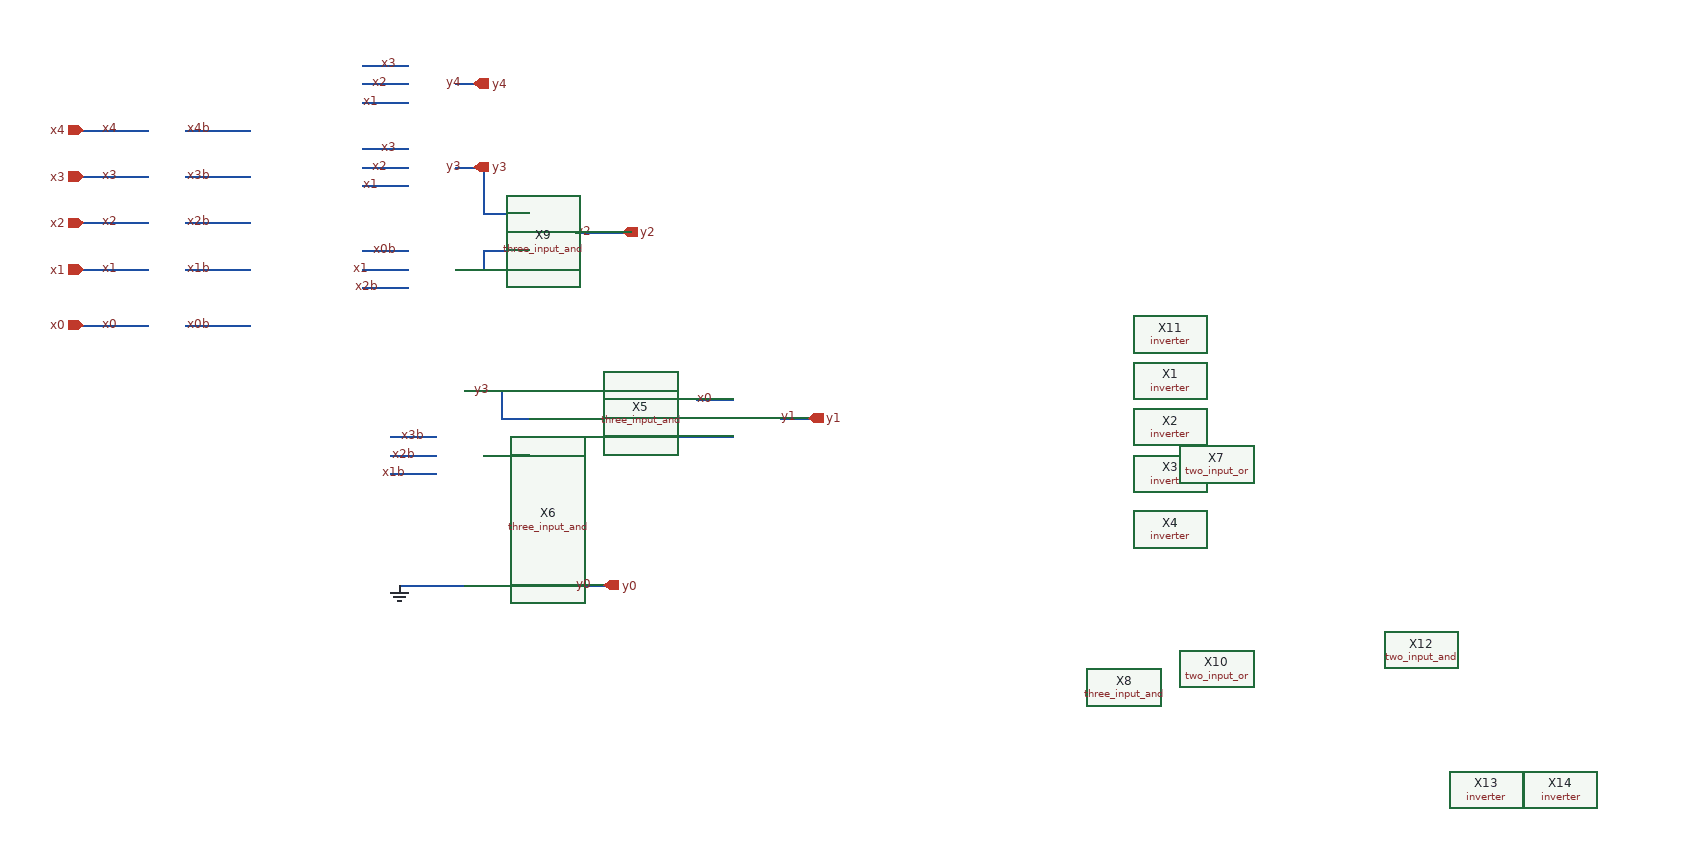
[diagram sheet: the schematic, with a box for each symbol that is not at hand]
v {xschem version=2.9.9 file_version=1.2 }
G {}
K {}
V {}
S {}
E {}
N -700 -240 -670 -240 { lab=x3}
N -630 -240 -580 -240 { lab=x3b}
N -750 -240 -700 -240 { lab=x3}
N -580 -240 -560 -240 { lab=x3b}
N -700 -190 -670 -190 { lab=x2}
N -630 -190 -580 -190 { lab=x2b}
N -750 -190 -700 -190 { lab=x2}
N -580 -190 -560 -190 { lab=x2b}
N -700 -140 -670 -140 { lab=x1}
N -630 -140 -580 -140 { lab=x1b}
N -750 -140 -700 -140 { lab=x1}
N -580 -140 -560 -140 { lab=x1b}
N -700 -80 -670 -80 { lab=x0}
N -630 -80 -580 -80 { lab=x0b}
N -750 -80 -700 -80 { lab=x0}
N -580 -80 -560 -80 { lab=x0b}
N -440 -270 -390 -270 { lab=x3}
N -440 -250 -390 -250 { lab=x2}
N -440 -230 -390 -230 { lab=x1}
N -340 -250 -310 -250 { lab=y3}
N -440 -160 -390 -160 { lab=x0b}
N -440 -140 -390 -140 { lab=x1}
N -440 -120 -390 -120 { lab=x2b}
N -340 -140 -310 -140 { lab=#net1}
N -310 -250 -310 -200 { lab=y3}
N -310 -200 -280 -200 { lab=y3}
N -280 -200 -260 -200 { lab=y3}
N -310 -160 -310 -140 { lab=#net1}
N -310 -160 -260 -160 { lab=#net1}
N -210 -180 -180 -180 { lab=y2}
N -330 -10 -290 -10 { lab=y3}
N -290 -10 -290 20 { lab=y3}
N -290 20 -260 20 { lab=y3}
N -300 60 -260 60 { lab=#net2}
N -210 40 -170 40 { lab=#net3}
N -170 40 -40 40 { lab=#net3}
N -80 0 -40 0 { lab=x0}
N 10 20 50 20 { lab=y1}
N -400 200 -330 200 { lab=GND}
N -290 200 -250 200 { lab=#net4}
N -210 200 -170 200 { lab=y0}
N -180 -180 -150 -180 { lab=y2}
N -410 40 -360 40 { lab=x3b}
N -410 60 -360 60 { lab=x2b}
N -410 80 -360 80 { lab=x1b}
N -310 60 -300 60 { lab=#net2}
N -440 -360 -390 -360 { lab=x3}
N -440 -340 -390 -340 { lab=x2}
N -440 -320 -390 -320 { lab=x1}
N -340 -340 -310 -340 { lab=y4}
N -700 -290 -670 -290 { lab=x4}
N -630 -290 -580 -290 { lab=x3b}
N -750 -290 -700 -290 { lab=x4}
N -580 -290 -560 -290 { lab=x3b}
C {/home/vinodhini/Documents/inverter.sym} 430 -20 0 0 {name=X1}
C {/home/vinodhini/Documents/inverter.sym} 430 30 0 0 {name=X2}
C {/home/vinodhini/Documents/inverter.sym} 430 80 0 0 {name=X3}
C {/home/vinodhini/Documents/inverter.sym} 430 140 0 0 {name=X4}
C {devices/lab_pin.sym} -700 -80 1 0 {name=l1 sig_type=std_logic lab=x0}
C {devices/lab_pin.sym} -700 -140 1 0 {name=l2 sig_type=std_logic lab=x1}
C {devices/lab_pin.sym} -700 -190 1 0 {name=l3 sig_type=std_logic lab=x2}
C {devices/lab_pin.sym} -700 -240 1 0 {name=l4 sig_type=std_logic lab=x3}
C {devices/lab_pin.sym} -600 -80 1 0 {name=l5 sig_type=std_logic lab=x0b}
C {devices/lab_pin.sym} -600 -140 1 0 {name=l6 sig_type=std_logic lab=x1b}
C {devices/lab_pin.sym} -600 -190 1 0 {name=l7 sig_type=std_logic lab=x2b}
C {devices/lab_pin.sym} -600 -240 1 0 {name=l8 sig_type=std_logic lab=x3b}
C {/home/vinodhini/Documents/three_input_and.symbol} 350 0 0 0 {name=X5}
C {devices/lab_pin.sym} -400 -270 1 0 {name=l9 sig_type=std_logic lab=x3}
C {devices/lab_pin.sym} -410 -250 1 0 {name=l10 sig_type=std_logic lab=x2}
C {devices/lab_pin.sym} -420 -230 1 0 {name=l11 sig_type=std_logic lab=x1}
C {devices/lab_pin.sym} -330 -250 1 0 {name=l12 sig_type=std_logic lab=y3}
C {/home/vinodhini/Documents/three_input_and.symbol} 350 110 0 0 {name=X6}
C {devices/lab_pin.sym} -400 -160 1 0 {name=l13 sig_type=std_logic lab=x0b}
C {devices/lab_pin.sym} -420 -120 1 0 {name=l15 sig_type=std_logic lab=x2b}
C {devices/lab_pin.sym} -430 -140 1 0 {name=l14 sig_type=std_logic lab=x1}
C {devices/lab_pin.sym} -190 -180 1 0 {name=l16 sig_type=std_logic lab=y2}
C {/home/vinodhini/Documents/two_input_or.symbol} 480 70 0 0 {name=X7}
C {/home/vinodhini/Documents/two_input_or.symbol} 480 290 0 0 {name=X10}
C {/home/vinodhini/Documents/two_input_and.symbol} 700 270 0 0 {name=X12}
C {devices/lab_pin.sym} 30 20 1 0 {name=l23 sig_type=std_logic lab=y1}
C {/home/vinodhini/Documents/inverter.sym} 770 420 0 0 {name=X13}
C {/home/vinodhini/Documents/inverter.sym} 850 420 0 0 {name=X14}
C {devices/lab_pin.sym} -190 200 1 0 {name=l24 sig_type=std_logic lab=y0}
C {devices/ipin.sym} -740 -80 0 0 {name=p1 lab=x0}
C {devices/ipin.sym} -740 -140 0 0 {name=p2 lab=x1}
C {devices/ipin.sym} -740 -190 0 0 {name=p3 lab=x2}
C {devices/ipin.sym} -740 -240 0 0 {name=p4 lab=x3}
C {devices/opin.sym} -320 -250 0 0 {name=p5 lab=y3}
C {devices/opin.sym} -160 -180 0 0 {name=p6 lab=y2}
C {devices/opin.sym} 40 20 0 0 {name=p7 lab=y1}
C {devices/opin.sym} -180 200 0 0 {name=p8 lab=y0}
C {devices/lab_pin.sym} -300 -10 1 0 {name=l17 sig_type=std_logic lab=y3}
C {/home/vinodhini/Documents/three_input_and.symbol} 380 310 0 0 {name=X8}
C {devices/lab_pin.sym} -370 40 1 0 {name=l19 sig_type=std_logic lab=x3b}
C {devices/lab_pin.sym} -380 60 1 0 {name=l20 sig_type=std_logic lab=x2b}
C {devices/lab_pin.sym} -390 80 1 0 {name=l21 sig_type=std_logic lab=x1b}
C {devices/lab_pin.sym} -60 0 1 0 {name=l18 sig_type=std_logic lab=x0}
C {devices/gnd.sym} -400 200 0 0 {name=l22 lab=GND}
C {/home/vinodhini/Documents/three_input_and.symbol} 350 -90 0 0 {name=X9}
C {devices/lab_pin.sym} -400 -360 1 0 {name=l25 sig_type=std_logic lab=x3}
C {devices/lab_pin.sym} -410 -340 1 0 {name=l26 sig_type=std_logic lab=x2}
C {devices/lab_pin.sym} -420 -320 1 0 {name=l27 sig_type=std_logic lab=x1}
C {devices/lab_pin.sym} -330 -340 1 0 {name=l28 sig_type=std_logic lab=y4}
C {devices/opin.sym} -320 -340 0 0 {name=p9 lab=y4}
C {/home/vinodhini/Documents/inverter.sym} 430 -70 0 0 {name=X11}
C {devices/lab_pin.sym} -700 -290 1 0 {name=l29 sig_type=std_logic lab=x4}
C {devices/lab_pin.sym} -600 -290 1 0 {name=l30 sig_type=std_logic lab=x4b}
C {devices/ipin.sym} -740 -290 0 0 {name=p10 lab=x4}
